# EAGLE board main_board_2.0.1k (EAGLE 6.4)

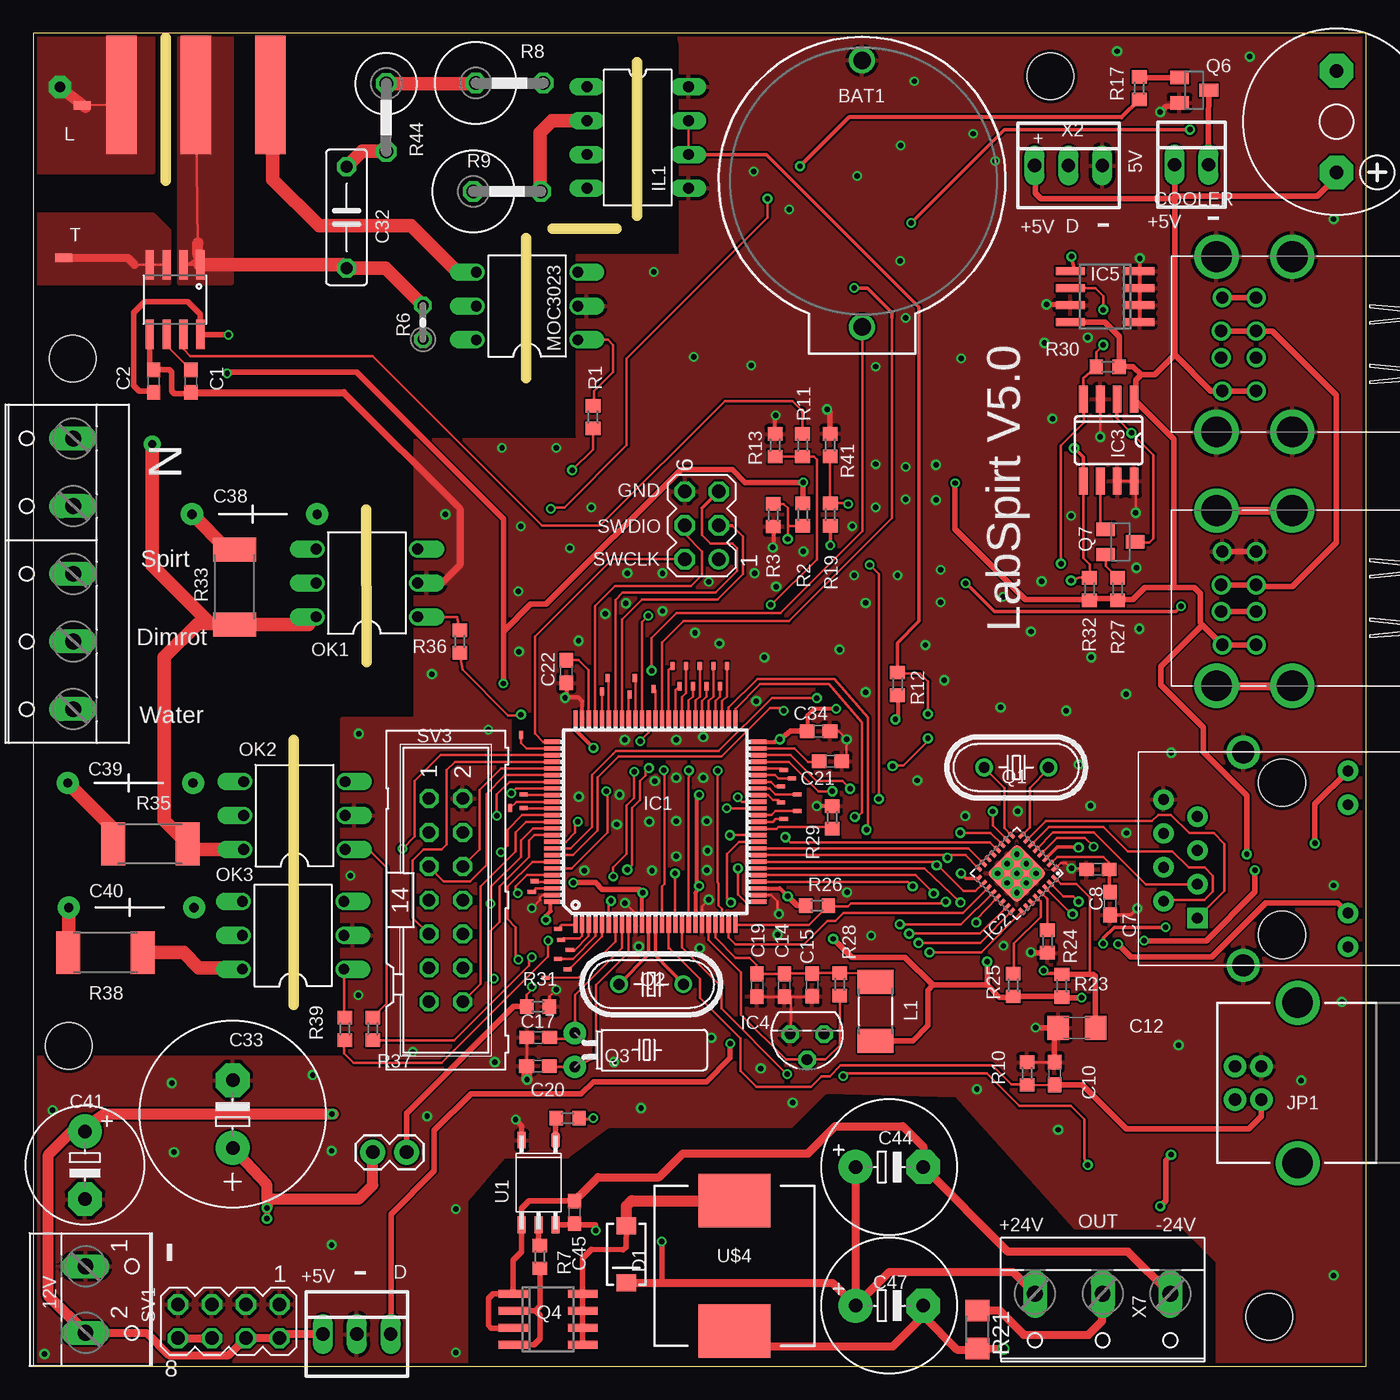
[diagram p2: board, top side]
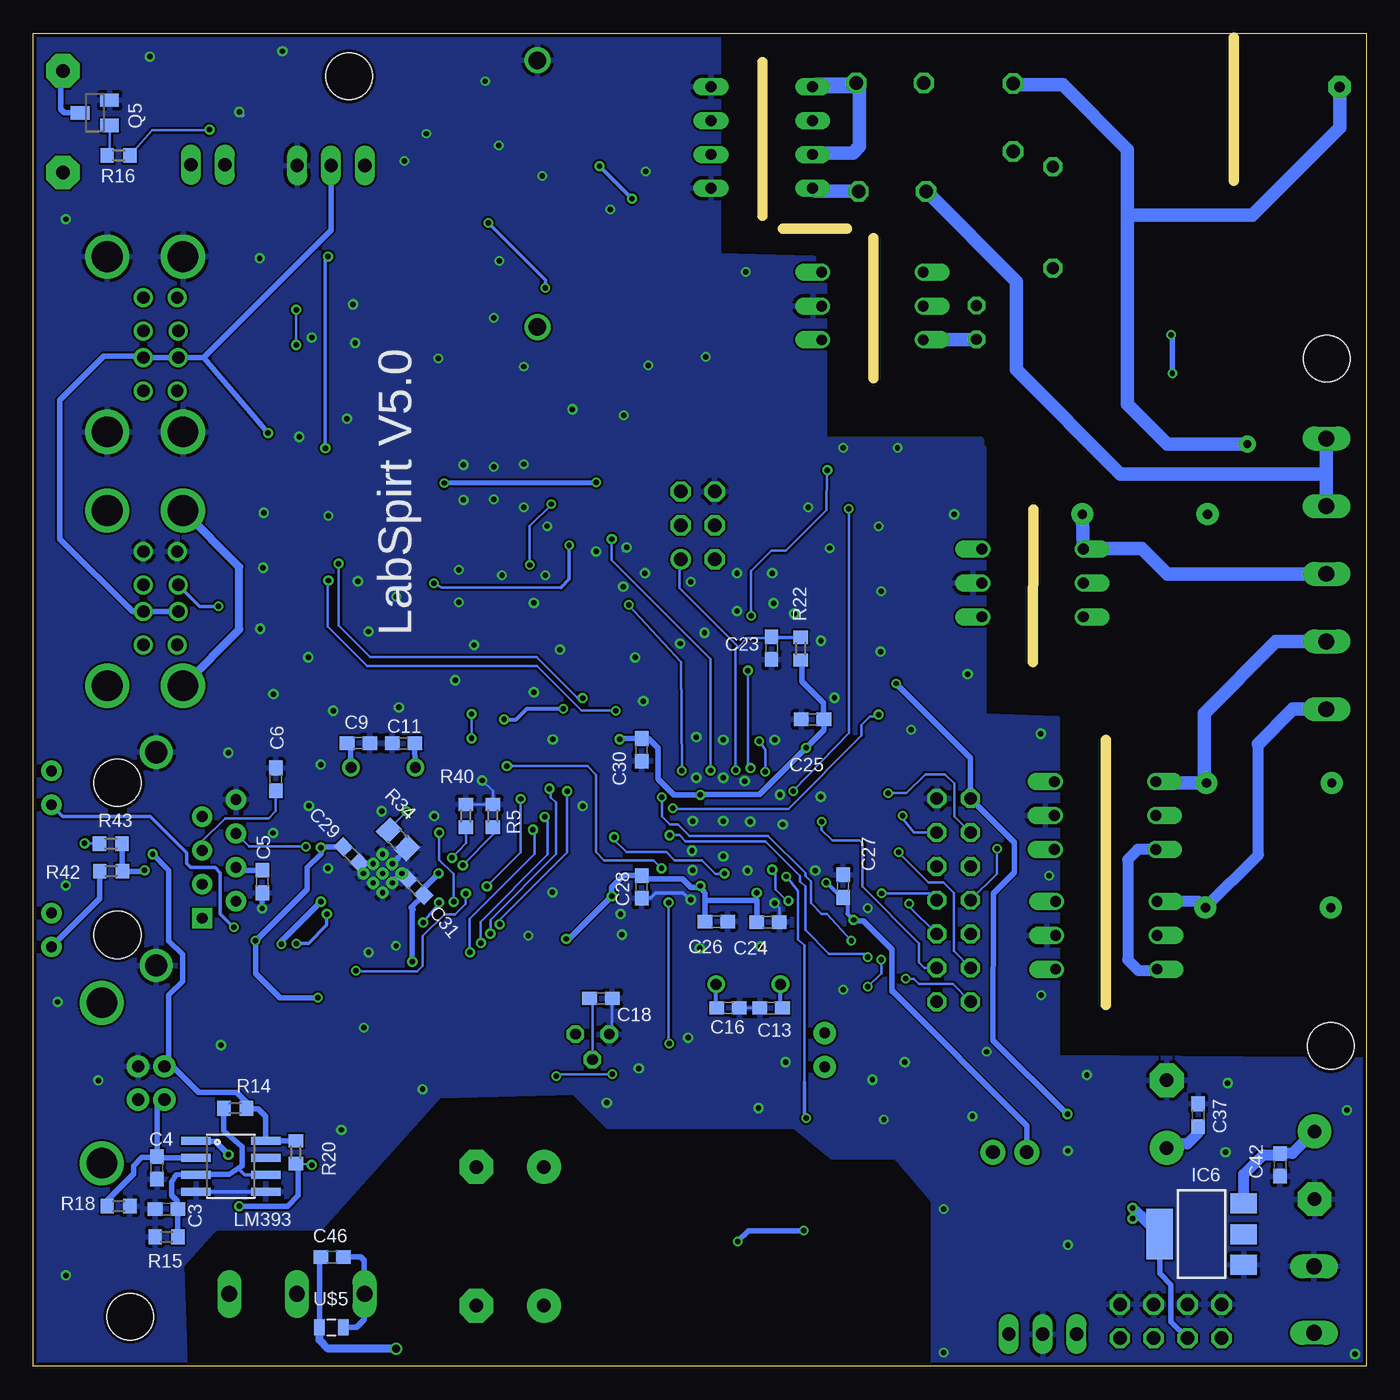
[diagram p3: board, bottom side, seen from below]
Size 100 x 100 mm. Coordinates in mm from the lower left corner, seen from the top.
Outline: 19.53,27.11 19.53,46.98
Outline: 25.02,52.82 24.96,64.29
Outline: 45.3,86.31 45.3,97.83
Outline: 36.97,74.12 36.97,84.62
Outline: 43.76,85.33 38.95,85.33
Outline: 9.94,88.95 9.94,99.66
Outline: 100,100 0,100 0,0 100,0 100,100
Copper layers (1*16): Top 0.035mm / dielectric 1.5mm / Bottom 0.035mm
Design rules "SeeedStudio_2layer_DRU_no_angle_20140221": minimum track width 6mil, minimum drill 12mil, track to track 6mil, track to pad 6mil, pad to pad 6mil, via to via 6mil, smd to smd 0mil, copper to edge 10mil, drill to drill 10mil, minimum pad ring 10mil, minimum via ring 6mil, stop-mask expansion 2mil, vias tented up to drill 100mil, thermal gap 10mil
Net classes: 0 default: width 0.203 mm, drill 0.203 mm, clearance 0.152 mm; 1 GND: width 0.203 mm, drill 0.203 mm, clearance 0.152 mm to class 0; 2 +3V3: width 0.254 mm, drill 0.203 mm, clearance 0.152 mm to class 0, clearance 0.152 mm to class 1; 3 +5V: width 0.406 mm, drill 0.152 mm, clearance 0.203 mm to class 0, clearance 0.203 mm to class 1, clearance 0.203 mm to class 2
Holes 3.5 mm at 76.32,96.76 2.65,24.02 92.73,3.72 2.97,75.6
tRestrict: area 73.8,35 to 76,39.2; 3 lines

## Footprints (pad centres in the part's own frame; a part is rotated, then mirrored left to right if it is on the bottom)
W237-102 = drill 1.194 long: 1 -2.5,-1.27; 2 2.5,-1.27
SO08 = smd 0.61 x 2.21: 1 -1.905,-2.616; 2 -0.635,-2.616; 3 0.635,-2.616; 4 1.905,-2.616; 5 1.905,2.616; 6 0.635,2.616; 7 -0.635,2.616; 8 -1.905,2.616
BATTCOM_20MM_PTH = drill 1.3: 1 20,0; 2 0,0
1X02 = drill 1.016 pad 1.88: 1 0,0; 2 2.54,0
C0603 = smd 1.1 x 1: 1 -0.85,0; 2 0.85,0
1206 = smd 1.6 x 1.8: 1 -1.4,0; 2 1.4,0
C075-032X103 = drill 0.914 octagon: 1 -3.81,0; 2 3.81,0
E5-13 = drill 1.016 pad 2.54: + -2.54,0 | drill 1.016 pad 2.54 octagon: - 2.54,0
CAP-PTH-LARGE = drill 0.7 pad 1.651: 1 -4.826,0; 2 4.572,0
E5-8,5 = drill 1.016 pad 2.54: + -2.54,0 | drill 1.016 pad 2.54 octagon: - 2.54,0
E5-10,5 = drill 1.016 pad 2.54: + -2.54,0 | drill 1.016 pad 2.54 octagon: - 2.54,0
22-23-2021 = drill 1 long: 1 -1.27,0; 2 1.27,0
SMA-DIODE = smd 1.27 x 1.47: A -2.15,0; C 2.15,0
LQFP100 = smd 1.2 x 0.32: 1 -7.75,6; 2 -7.75,5.5; 3 -7.75,5; 4 -7.75,4.5; 5 -7.75,4; 6 -7.75,3.5; 7 -7.75,3; 8 -7.75,2.5; 9 -7.75,2; 10 -7.75,1.5; 11 -7.75,1; 12 -7.75,0.5; 13 -7.75,0; 14 -7.75,-0.5; 15 -7.75,-1; 16 -7.75,-1.5; 17 -7.75,-2; 18 -7.75,-2.5; 19 -7.75,-3; 20 -7.75,-3.5; 21 -7.75,-4; 22 -7.75,-4.5; 23 -7.75,-5; 24 -7.75,-5.5; 25 -7.75,-6; 51 7.75,-6; 52 7.75,-5.5; 53 7.75,-5; 54 7.75,-4.5; 55 7.75,-4; 56 7.75,-3.5; 57 7.75,-3; 58 7.75,-2.5; 59 7.75,-2; 60 7.75,-1.5; 61 7.75,-1; 62 7.75,-0.5; 63 7.75,0; 64 7.75,0.5; 65 7.75,1; 66 7.75,1.5; 67 7.75,2; 68 7.75,2.5; 69 7.75,3; 70 7.75,3.5; 71 7.75,4; 72 7.75,4.5; 73 7.75,5; 74 7.75,5.5; 75 7.75,6 | smd 0.32 x 1.2: 26 -6,-7.75; 27 -5.5,-7.75; 28 -5,-7.75; 29 -4.5,-7.75; 30 -4,-7.75; 31 -3.5,-7.75; 32 -3,-7.75; 33 -2.5,-7.75; 34 -2,-7.75; 35 -1.5,-7.75; 36 -1,-7.75; 37 -0.5,-7.75; 38 0,-7.75; 39 0.5,-7.75; 40 1,-7.75; 41 1.5,-7.75; 42 2,-7.75; 43 2.5,-7.75; 44 3,-7.75; 45 3.5,-7.75; 46 4,-7.75; 47 4.5,-7.75; 48 5,-7.75; 49 5.5,-7.75; 50 6,-7.75; 76 6,7.75; 77 5.5,7.75; 78 5,7.75; 79 4.5,7.75; 80 4,7.75; 81 3.5,7.75; 82 3,7.75; 83 2.5,7.75; 84 2,7.75; 85 1.5,7.75; 86 1,7.75; 87 0.5,7.75; 88 0,7.75; 89 -0.5,7.75; 90 -1,7.75; 91 -1.5,7.75; 92 -2,7.75; 93 -2.5,7.75; 94 -3,7.75; 95 -3.5,7.75; 96 -4,7.75; 97 -4.5,7.75; 98 -5,7.75; 99 -5.5,7.75; 100 -6,7.75
QFN32 = smd 0.6 x 0.3: 1 -2.3,1.75; 2 -2.3,1.25; 3 -2.3,0.75; 4 -2.3,0.25; 5 -2.3,-0.25; 6 -2.3,-0.75; 7 -2.3,-1.25; 8 -2.3,-1.75; 17 2.3,-1.75; 18 2.3,-1.25; 19 2.3,-0.75; 20 2.3,-0.25; 21 2.3,0.25; 22 2.3,0.75; 23 2.3,1.25; 24 2.3,1.75 | smd 0.3 x 0.6: 9 -1.75,-2.3; 10 -1.25,-2.3; 11 -0.75,-2.3; 12 -0.25,-2.3; 13 0.25,-2.3; 14 0.75,-2.3; 15 1.25,-2.3; 16 1.75,-2.3; 25 1.75,2.3; 26 1.25,2.3; 27 0.75,2.3; 28 0.25,2.3; 29 -0.25,2.3; 30 -0.75,2.3; 31 -1.25,2.3; 32 -1.75,2.3 | smd 3.2 x 3.2: G 0,0 | drill 0.4: P$2 -1.016,1.016; P$3 0,1.016; P$4 1.016,1.016; P$5 -1.016,0; P$6 -1.016,-1.016; P$7 0,0; P$8 0,-1.016; P$9 1.016,0; P$10 1.016,-1.016
SO08' = smd 0.66 x 2.032: 1 -1.905,-3.073; 2 -0.635,-3.073; 3 0.635,-3.073; 4 1.905,-3.073; 5 1.905,3.073; 6 0.635,3.073; 7 -0.635,3.073; 8 -1.905,3.073
TO92 = drill 0.813 octagon: 1 -1.27,0; 2 0,1.905; 3 1.27,0
SO-08 = smd 0.6 x 2.2: 1 -1.905,-2.6; 2 -0.635,-2.6; 3 0.635,-2.6; 4 1.905,-2.6; 5 1.905,2.6; 6 0.635,2.6; 7 -0.635,2.6; 8 -1.905,2.6
SOT223 = smd 1.5 x 2: 1 -2.3,-3.15; 2 0,-3.15; 3 2.3,-3.15 | smd 3.8 x 2: 4 0,3.15
DIL8 = drill 0.813 long: 1 -3.81,-3.81; 2 -1.27,-3.81; 3 1.27,-3.81; 4 3.81,-3.81; 5 3.81,3.81; 6 1.27,3.81; 7 -1.27,3.81; 8 -3.81,3.81
USB-B-PTH = drill 0.914 pad 1.676: D+ 0,1.25; D- 1.981,1.25; GND 0,-1.25; VBUS 1.981,-1.25 | drill 2.286: S1 -2.718,-6.02; S2 -2.718,6.02
PAD-220 = smd 0.635 x 1.27: 1 0,0
R2010 = smd 1.8 x 2.7: 1 -2.2,0; 2 2.2,0
DIL06 = drill 0.813 offset: 1 -2.54,-3.81; 2 0,-3.81; 3 2.54,-3.81; 4 2.54,3.81; 5 0,3.81; 6 -2.54,3.81
HC49U-V = drill 0.813: 1 -2.413,0; 2 2.413,0
TC38H = drill 0.813 pad 1.676: 1 -1.27,0; 2 1.27,0
SOT23 = smd 1 x 1.4: 1 -0.95,-1.1; 2 0.95,-1.1; 3 0,1.1
R0603 = smd 1 x 1.1: 1 -0.85,0; 2 0.85,0
0204V = drill 0.813 octagon: 1 -1.27,0; 2 1.27,0
0617V = drill 1.016 octagon: 1 -2.54,0; 2 2.54,0
R1206 = smd 1.6 x 1.803: 1 -1.422,0; 2 1.422,0
R2512 = smd 1.8 x 3.2: 1 -2.8,0; 2 2.8,0
R0805 = smd 1.3 x 1.5: 1 -0.95,0; 2 0.95,0
P0613V = drill 1.016 octagon: 1 -2.54,0; 2 2.54,0
HR911105A = drill 0.813 pad 1.524: G+ 4.953,-6.604; G- 4.953,-4.064; GND -8.89,4.445; NC -6.35,3.175; P4 -8.89,-0.635; P5 -6.35,0.635; RD+ -6.35,-1.905; RD- -8.89,1.905; TD- -8.89,-3.175; Y+ 4.953,6.604; Y- 4.953,4.064 | drill 1.651 pad 2.159: SHIELD0 -2.921,8.001; SHIELD1 -2.921,-8.001 | drill 0.813 pad 1.524 square: TD+ -6.35,-4.445 | hole 3.556: 0,-5.715; 0,5.715
F/CM12P = drill 1.016 pad 2.54 octagon: + 3.81,0; - -3.81,0
MA04-2 = drill 1.016 octagon: 1 -3.81,-1.27; 2 -3.81,1.27; 3 -1.27,-1.27; 4 -1.27,1.27; 5 1.27,-1.27; 6 1.27,1.27; 7 3.81,-1.27; 8 3.81,1.27
MA03-2 = drill 1.016: 1 -2.54,-1.27 | drill 1.016 octagon: 2 -2.54,1.27; 3 0,-1.27; 4 0,1.27; 5 2.54,-1.27; 6 2.54,1.27
ML14 = drill 0.914 octagon: 1 -7.62,-1.27; 2 -7.62,1.27; 3 -5.08,-1.27; 4 -5.08,1.27; 5 -2.54,-1.27; 6 -2.54,1.27; 7 0,-1.27; 8 0,1.27; 9 2.54,-1.27; 10 2.54,1.27; 11 5.08,-1.27; 12 5.08,1.27; 13 7.62,-1.27; 14 7.62,1.27
MY = smd 0.305 x 0.61: P$1 0,0
PANASONIC_SOP5 = smd 0.6 x 1.25: 1 -1.27,-3.175; 2 1.27,-3.175; 3 1.27,3.175; 4 0,3.175; 5 -1.27,3.175
TOP3L = smd 2.286 x 8.89: A1 -5.334,-0.508; A2 0.254,-0.508; G3 5.842,-0.508
CDRH125 = smd 5.4 x 4: 1 0,4.9; 2 0,-4.9
0805 = smd 0.8 x 1.2: 1 -0.9,0; 2 0.9,0
22-23-2031 = drill 1 long: 1 -2.54,0; 2 0,0; 3 2.54,0
W237-5P = drill 1.194 long: 1 -10.16,-0.635; 2 -5.08,-0.635; 3 0,-0.635; 4 5.08,-0.635; 5 10.16,-0.635
85-32003-00X-1 = drill 0.92 pad 1.27: 1-1 2.71,3.5; 1-2 2.71,1; 1-3 2.71,-1; 1-4 2.71,-3.5; 1-5 5.25,3.5; 1-6 5.33,1; 1-7 5.33,-1; 1-8 5.25,-3.5 | drill 2.3 pad 3: M1 0,6.57; M2 0,-6.57; M3 5.68,6.57; M4 5.68,-6.57
W237-133 = drill 1.194 long: 1 -5.08,-0.635; 2 0,-0.635; 3 5.08,-0.635

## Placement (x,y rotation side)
12V  [W237-102]  5.18,4.99 270 top
$1_103_$  ACS712  [SO08]  10.63,80.02 180 top
BAT1  3.3V  [BATTCOM_20MM_PTH]  62.18,97.97 270 top
BOOT  M02PTH  [1X02]  25.47,16.05 0 top
C1  0.01uF  [C0603]  11.82,73.9 90 top
C2  0.1uF  [C0603]  9.03,73.9 270 top
C3  0.1uF  [C0603]  90,11.79 0 bottom
C4  0.1uF  [C0603]  90.72,14.88 90 bottom
C5  0.1uF  [C0603]  82.82,36.36 270 bottom
C6  0.1uF  [C0603]  81.8,44.03 90 bottom
C7  2.2uF  [C0603]  80.79,34.71 90 top
C8  0.1uF  [C0603]  79.87,37.27 0 top
C9  22pF  [C0603]  75.61,46.75 0 bottom
C10  0.1uF  [C0603]  76.62,21.96 270 top
C11  22pF  [C0603]  72.22,46.73 180 bottom
C12  10uF  [1206]  78.29,25.39 0 top
C13  22pF  [C0603]  44.64,26.88 180 bottom
C14  1uF  [C0603]  56.35,28.58 90 top
C15  1uF  [C0603]  58.43,28.6 270 top
C16  22pF  [C0603]  47.88,26.88 0 bottom
C17  6.8pF  [C0603]  37.88,24.66 180 top
C18  0.1uF  [C0603]  57.42,27.6 180 bottom
C19  0.1uF  [C0603]  54.29,28.58 270 top
C20  6.8pF  [C0603]  37.86,22.52 180 top
C21  2.2uF  [C0603]  59.81,45.38 0 top
C22  2.2uF  [C0603]  39.99,52.12 270 top
C23  0.1uF  [C0603]  44.62,53.89 270 bottom
C24  0.1uF  [C0603]  44.88,33.31 180 bottom
C25  0.1uF  [C0603]  41.53,48.53 180 bottom
C26  0.1uF  [C0603]  48.76,33.35 180 bottom
C27  0.1uF  [C0603]  39.24,36.02 90 bottom
C28  0.1uF  [C0603]  54.36,35.96 90 bottom
C29  0.1uF  [C0603]  76.14,38.37 315 bottom
C30  0.1uF  [C0603]  54.36,46.24 90 bottom
C31  0.1uF  [C0603]  71.31,35.96 135 bottom
C32  0.01uF  [C075-032X103]  23.51,86.19 90 top
C33  4700uF/6.3V  [E5-13]  14.96,18.91 90 top
C34  4.7uF  [C0603]  58.92,47.64 0 top
C37  0.1uF  [C0603]  12.61,18.84 270 bottom
C38  0.01uF  [CAP-PTH-LARGE]  16.47,63.92 180 top
C39  0.01uF  [CAP-PTH-LARGE]  7.15,43.75 180 top
C40  0.01uF  [CAP-PTH-LARGE]  7.23,34.4 180 top
C41  1000uF/10V  [E5-8,5]  3.87,15.08 270 top
C42  0.1uF  [C0603]  6.46,15.1 90 bottom
C44  220uF/35  [E5-10,5]  64.22,14.95 0 top
C45  0.1uF  [C0603]  40.6,11.54 270 top
C46  0.1uF  [C0603]  77.58,8.19 0 bottom
C47  220uF/63  [E5-10,5]  64.22,4.53 0 top
COOLER  22-23-2021  [22-23-2021]  86.9,90.14 0 top
D1  SS36  [SMA-DIODE]  44.49,8.39 270 top
IC1  STM32F407  [LQFP100]  46.67,40.85 90 top
IC2  KSZ8051RNL  [QFN32]  73.79,36.97 225 top
IC3  DS2428  [SO08']  80.68,69.47 180 top
IC4  LM336LP  [TO92]  58.05,24.91 180 top
IC5  24LC64SN  [SO-08]  80.4,80.25 90 top
IC6  LD117AS33TR  [SOT223]  12.34,9.91 90 bottom
IL1  MCT62  [DIL8]  45.35,92.18 270 top
JP1  USB-B  [USB-B-PTH]  92.14,21.25 180 top
L  PAD-220  [PAD-220]  3.68,94.6 270 top
L1  47u  [R2010]  63.2,26.62 90 top
LM393  LM393  [SO08]  85.18,15 270 bottom
MOC3023  IL410  [DIL06]  37.05,79.54 90 top
OK1  MOC3063  [DIL06]  25.03,58.76 90 top
OK2  MOC3063  [DIL06]  19.6,41.31 90 top
OK3  MOC3063  [DIL06]  19.49,32.32 90 top
Q1  25Mhz  [HC49U-V]  73.75,44.92 180 top
Q2  25Mhz  [HC49U-V]  46.36,28.65 0 top
Q3  [TC38H]  40.63,23.73 270 top
Q4  IRF7103  [SO-08]  38.62,3.52 270 top
Q5  BC847  [SOT23]  95.38,94.03 90 bottom
Q6  BC847  [SOT23]  87.1,95.73 270 top
Q7  BSS84  [SOT23]  81.56,61.84 270 top
R1  200  [R0603]  41.99,71.21 90 top
R2  4.7k  [R0603]  57.74,63.9 270 top
R3  4.7k  [R0603]  55.52,63.84 270 top
R4  200  [R0603]  40.09,18.61 180 top
R5  1k  [R0603]  65.52,41.29 270 bottom
R6  180  [0204V]  29.24,78.31 90 top
R7  [R0603]  38.01,8.19 270 top
R8  33k  [0617V]  35.73,96.27 0 top
R9  33k  [0617V]  35.55,88.14 0 top
R10  10k  [R0603]  74.56,21.96 90 top
R11  4.7k  [R0603]  57.71,69.09 270 top
R12  4.3k  [R0603]  64.84,51.19 270 top
R13  4.7k  [R0603]  55.65,69.09 90 top
R14  15k  [R0603]  84.86,19.34 0 bottom
R15  1.5k  [R0603]  90.01,9.7 0 bottom
R16  1k  [R0603]  93.6,90.83 180 bottom
R17  1k  [R0603]  82.98,95.88 90 top
R18  1M  [R0603]  93.61,12 180 bottom
R19  4.7k  [R0603]  59.8,63.89 90 top
R20  4.3k  [R0603]  80.3,16.05 90 bottom
R21  0  [R1206]  70.83,2.76 270 top
R22  10k  [R0603]  42.43,53.84 90 bottom
R23  10k  [R0603]  77.17,28.55 90 top
R24  1k  [R0603]  76.09,31.86 90 top
R25  4.7k  [R0603]  73.52,28.59 90 top
R26  1k  [R0603]  58.8,34.56 180 top
R27  1R  [R0603]  81.34,58.3 90 top
R28  4.3k  [R0603]  60.5,28.64 270 top
R29  100R  [R0603]  59.95,41.16 90 top
R30  4.3k  [R0603]  80.6,74.97 180 top
R31  100R  [R0603]  37.87,26.99 0 top
R32  4.3k  [R0603]  79.24,58.31 90 top
R33  39  [R2512]  15.1,58.46 90 top
R34  6.49k  [R0805]  72.64,39.52 135 bottom
R35  39  [R2512]  8.78,39.18 180 top
R36  200  [R0603]  31.99,54.37 90 top
R37  200  [R0603]  25.46,25.31 90 top
R38  39  [R2512]  5.42,31.03 180 top
R39  200  [R0603]  23.38,25.31 90 top
R40  1k  [R0603]  67.55,41.29 90 bottom
R41  4.7k  [R0603]  59.78,69.1 90 top
R42  220  [R0603]  94.17,37.15 0 bottom
R43  220  [R0603]  94.2,39.2 0 bottom
R44  39  [P0613V]  26.48,93.69 270 top
RJ1  HR911105A  [HR911105A]  93.69,38.06 0 top
SG1  F/CM12P  [F/CM12P]  97.78,93.37 270 top
SV1  [MA04-2]  14.67,3.37 180 top
SV2  [MA03-2]  50.15,63.08 90 top
SV3  [ML14]  30.95,34.96 270 top
T  PAD-220  [PAD-220]  2.28,83.15 270 top
TP1  PTR1MY0012X0024  [MY]  39.59,31.97 90 top
TP2  PTR1MY0012X0024  [MY]  40.25,31.23 90 top
TP3  PTR1MY0012X0024  [MY]  39.36,30.57 90 top
TP4  PTR1MY0012X0024  [MY]  40.07,29.76 90 top
TP5  PTR1MY0012X0024  [MY]  38.44,29.15 90 top
TP6  PTR1MY0012X0024  [MY]  56.3,41.06 90 top
TP7  PTR1MY0012X0024  [MY]  57.32,41.67 90 top
TP8  PTR1MY0012X0024  [MY]  56.1,42.28 90 top
TP9  PTR1MY0012X0024  [MY]  57.32,42.89 90 top
TP10  PTR1MY0012X0024  [MY]  56.1,43.5 270 top
TP11  PTR1MY0012X0024  [MY]  56.91,44.11 90 top
TP12  PTR1MY0012X0024  [MY]  56.3,44.72 90 top
TP13  PTR1MY0012X0024  [MY]  52.03,52.54 180 top
TP14  PTR1MY0012X0024  [MY]  46.55,50.81 0 top
TP15  PTR1MY0012X0024  [MY]  45.12,51.63 0 top
TP16  PTR1MY0012X0024  [MY]  44.72,50.41 0 top
TP17  PTR1MY0012X0024  [MY]  43.09,51.63 0 top
TP18  PTR1MY0012X0024  [MY]  42.68,50.61 0 top
TP19  PTR1MY0012X0024  [MY]  36.59,47.36 0 top
TP20  PTR1MY0012X0024  [MY]  36.79,42.89 90 top
TP21  PTR1MY0012X0024  [MY]  35.78,41.87 180 top
TP22  PTR1MY0012X0024  [MY]  36.79,41.87 270 top
TP23  PTR1MY0012X0024  [MY]  37.6,36.39 90 top
TP24  PTR1MY0012X0024  [MY]  37.4,35.57 90 top
TP25  PTR1MY0012X0024  [MY]  39.36,32.8 90 top
TP26  PTR1MY0012X0024  [MY]  51.52,51.02 0 top
TP27  PTR1MY0012X0024  [MY]  51.02,52.54 0 top
TP28  PTR1MY0012X0024  [MY]  50.51,51.02 0 top
TP29  PTR1MY0012X0024  [MY]  50,52.54 0 top
TP30  PTR1MY0012X0024  [MY]  49.49,51.02 0 top
TP31  PTR1MY0012X0024  [MY]  48.98,52.54 0 top
TP32  PTR1MY0012X0024  [MY]  48.48,51.02 0 top
TP33  PTR1MY0012X0024  [MY]  47.97,52.54 0 top
U1  LTV-155E  [PANASONIC_SOP5]  37.91,13.78 180 top
U$1  BTA-41  [TOP3L]  11.94,95.9 0 top
U$4  [CDRH125]  52.59,7.53 0 top
U$5  DIODE_0806  [0805]  77.64,2.91 0 bottom
X1  22-23-2031  [22-23-2031]  24.27,2.4 0 top
X2  22-23-2031  [22-23-2031]  77.66,90.08 0 top
X3  [W237-5P]  2.35,59.45 90 top
X5  USB_3PSHIELD-85-32003-00X-1  [85-32003-00X-1]  94.45,57.62 180 top
X6  USB_3PSHIELD-85-32003-00X-1  [85-32003-00X-1]  94.45,76.67 180 top
X7  [W237-133]  80.23,4.79 180 top

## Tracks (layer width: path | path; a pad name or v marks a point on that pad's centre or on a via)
1WIRE  (via drill 0.41 pad 0.76)
  Top 0.203: 81.32,71.08 v82.38,70.02 84.04,68.36 84.04,62.09 83.73,61.79 82.71,61.79 Q7.3 | 81.32,71.08 IC3.2 81.24,72.47 81.24,71.16 81.32,71.08
  Top 0.406: X5.1-6 X5.1-2
  Bottom 0.203: 91.85,75.78 X6.1-2
  Bottom 0.406: X6.1-2 X6.1-6 87.23,75.67 | v82.38,70.02 87.23,75.67 | X5.1-6 92.56,56.62 98.01,62.06 98.01,72.48 94.7,75.78 91.85,75.78 | X2.2 77.66,85.24 87.23,75.67
+3V3  (via drill 0.41, 0.41 pad 0.76)
  Top 0.254: IC2.17 69.99,36.58 v69.6,36.97 | IC2.3 76.85,38.97 78.14,38.97 v78.42,38.91 | 40.67,47.73 IC1.75
  Top 0.305: IC1.19 49.67,35.5 v49.95,36.03 49.77,36.34 49.77,42.69 v49.95,42.87 | IC1.50 55.63,46.85 v56.01,47.04 | 40.67,47.73 v42.02,46.39 | R12.2 64.88,50.29 64.88,48.73 v64.68,48.53 | 58.14,47.68 C34.1 58.08,47.65 58.08,48.83 58.56,49.31 v60.24,49.31 | IC1.28 56.01,35.85 v56.6,35.25 | v38.46,33.48 38.46,33.78 38.82,34.15 38.82,34.75 IC1.100 | IC1.11 45.67,35.46 v45.72,35.51
  Top 0.406: v56.01,47.04 56.81,47.65 C34.1 | 71.57,28.59 67.5,28.59 | v60.01,32.06 60.03,32.06 61.41,30.69 65.41,30.69 67.5,28.59 | v71.57,30.36 71.57,28.59 | 71.57,28.59 72.49,27.66 73.44,27.66 R25.1 77.13,27.74 R23.1 77.22,27.65 v78.65,27.65 | v17.52,11.88 v17.52,11.06 | R26.2 57.29,34.56 v56.6,35.25 | L1.1 65.98,24.42 67.12,25.57 67.12,28.21 67.5,28.59 | v91.66,37.2 91.66,35.57 88,31.91 v83.33,31.91 | v40.5,36.28 42.18,36.28 42.69,35.78 45.46,35.78 v45.72,35.51
  Top 0.61: SV1.8 SV1.6
  Top 0.813: 17.53,12.54 v17.52,11.88 | 17.53,12.54 17.53,13.59 C33.+ | 17.53,12.54 24.43,12.54 25.46,13.58 BOOT.1
  Bottom 0.254: 93.35,37.17 R42.2 | v78.42,38.91 78.42,38.85
  Bottom 0.305: 45.72,34.93 v45.72,35.51 | v38.46,33.48 38.92,33.95 IC1.100 C27.1 39.39,35.17 v40.5,36.28 | v64.68,48.53 63.77,48.53 62.95,49.34 60.26,49.34 v60.24,49.31
  Bottom 0.406: C24.2 45.72,33.77 45.72,34.93 49.59,34.93 | C26.2 49.59,33.81 49.59,34.93 | C30.2 55.76,47.09 v56.01,47.04 | 54.12,47.32 54.22,47.22 C30.2 | 40.6,48.34 C25.1 | 76.92,38.89 76.82,38.89 C29.1 78.39,38.97 v78.42,38.91 78.42,38.44 79.46,37.4 79.46,35.78 v83.33,31.91 83.33,29.48 81.5,27.65 v78.65,27.65 | 49.75,35.64 v49.95,36.03 | v71.57,30.36 71.57,34.22 71.5,34.28 71.64,34.42 70.73,35.33 C31.1 70.71,35.86 v69.6,36.97 | C30.2 53.85,47.09 53.12,46.37 53.12,44.06 51.93,42.87 v49.95,42.87 49.93,42.89 45.53,42.89 v42.03,46.39 v42.02,46.39 40.68,47.73 C25.1 | 49.59,34.93 49.59,35.47 v49.95,36.03 | R43.2 93.35,37.17 | IC6.4 15.49,6.96 14.64,6.11 14.64,3.34 SV1.6 | C37.2 12.61,17.49 | 14.66,16.67 C33.+ | C25.1 IC1.75 40.7,48.62 40.7,49.75 42.33,51.37 42.33,52.88 R22.1 42.42,53 | R42.2 93.28,37.11 91.75,37.11 v91.66,37.2 | v60.01,32.06 59.79,32.06 v56.6,35.25 56.61,35.59 56.61,35.91 55.7,36.81 C28.2 54.22,36.76 54.02,36.55 51.28,36.55 50.66,35.93 50.05,35.93 v49.95,36.03 | v38.46,33.48 38.37,33.39 37.71,33.39 35.57,31.25 35.57,28.11 35.52,28.11 25.47,18.05 BOOT.1
  Bottom 0.813: v17.52,11.88 IC6.4 | 12.61,17.49 13.42,16.67 14.66,16.67
+3V3A
  Top 0.203: L1.2 63.14,29.46 R28.1 58.47,29.49 C15.1 56.38,29.45 C14.2 C19.1 54.26,29.47 54.26,30.11 53.72,30.64 52.69,30.64 51.17,32.16 IC1.22
+5V  (via drill 0.41, 0.41 pad 0.76)
  Top 0.406: R27.1 81.48,57.59 | R32.1 79.5,57.59 81.2,57.59 R27.1 | 81.56,75.07 81.5,75.01 | 81.24,57.61 R27.1 | 12.49,77.6 $1_103_$.8 | 85.59,58.41 87.11,58.41 87.54,57.98 87.54,55.78 87.71,55.61 | 85.59,58.41 85.59,69.54 IC3.1 82.72,72.67 82.72,73.98 83.12,74.38 | 18.78,2.4 SV1.2 | 74.9,90.3 X2.1 | X2.1 75.12,89.7 | 79.28,57.42 R32.1 | R32.1 79.17,57.52 74.44,57.52 69.15,62.8 v69.15,66.26 | 85.59,58.41 83.4,58.41 82.51,57.52 81.41,57.52 R27.1 | v91.05,38.42 91.05,42.84 87.8,46.09 87.8,47.92 84.59,51.12 84.59,52.49 87.71,55.61 | X2.1 75.2,90 75.2,88 75.6,87.59 85.43,87.59 85.63,87.39 | 87.71,55.61 X5.1-5 X5.1-1 | v35.27,51.22 35.27,55.13 | 35.27,55.13 37.3,57.16 38.47,57.16 48.58,67.27 52.44,67.27 53.4,66.31 v57.75,66.31 R2.1 | 35.27,55.13 35.27,63.56 24.24,74.59 14.64,74.59 v14.54,74.49 | v14.64,77.38 12.56,77.38 $1_103_$.8 | $1_103_$.8 12.53,78.93 11.59,79.87 8.34,79.87 7.53,79.06 7.53,73.57 7.94,73.16 8.92,73.16 C2.2 | IC5.8 80.38,78.35 81.5,77.23 81.5,75.01 | 81.5,75.01 R30.1 | X6.1-1 X6.1-5 88.35,73.17 85.63,75.88 | COOLER.1 85.63,87.59 | 85.63,87.59 85.63,87.39 | 85.63,87.39 85.63,75.88 | SG1.+ 97.78,89.24 96.33,87.8 85.84,87.8 85.63,87.59 | 85.63,75.88 84.14,74.38 83.12,74.38 | 81.5,75.01 82.5,75.01 83.12,74.38
  Top 0.61: 12V.2 8.51,2.49 10.17,0.83 14.67,0.83 SV1.4 SV1.2 | X1.1 18.78,2.4
  Top 0.813: 12V.2 1.13,5.28 1.13,15.86 2.88,17.62 C41.+ 4.08,17.82 4.08,18.1 5.3,18.91 v22.42,18.91 22.52,18.91
  Bottom 0.406: IC6.3 | 89.83,22.57 89.42,22.36 87.59,20.54 84.75,20.54 84.01,19.8 R14.2 83.98,19.32 83.12,19.32 82.56,18.76 LM393.8 82.56,16.83 81.85,16.83 81.85,16.9 R20.2 | 89.83,22.57 90.03,22.36 JP1.VBUS | v91.05,38.42 89.83,37.2 89.83,31.91 88.81,30.9 88.81,28.87 89.83,27.85 89.83,22.57 | v22.42,18.91 28,24.45 27.95,35.47 26.38,37.05 26.38,39.28 SV3.1 29.68,45.63 v35.27,51.22 | v69.15,66.26 v57.75,66.31 | v14.54,74.49 14.54,77.28 v14.64,77.38
  Bottom 0.813: C41.+ 5.54,15.95 C42.2 6.55,15.86 7.73,15.86 9.19,14.4 IC6.3
+24V  (via drill 0.41)
  Top 0.406: U1.5 40.51,10.6 | 40.51,10.6 C45.2 | 40.51,10.6 42.18,10.6 v42.2,10.17 | v47.16,9.36 47.16,6.45 47.36,6.24
  Top 0.61: D1.C 47.36,6.24 59.97,6.24 C47.+ | C44.+ C47.+ | C47.+ 64.22,7.07 73.5,7.07 X7.3
  Bottom 0.406: U$5.2 75.76,2.91 75.2,3.47 75.2,5.37 X7.3 75.2,5.47 75.2,7.94 75.45,8.19 C46.2 | v42.2,10.17 46.34,10.17 v47.16,9.36
-24
  Top 0.406: Q4.3 35.99,2.86 34.35,2.86 34.15,3.06 34.15,5.09 34.48,5.42 Q4.1 35.98,5.47 35.98,7.94 36.64,8.6 U1.3 36.64,11.85 37.2,12.41 40.59,12.41 C45.1
  Top 0.61: X7.1 82.13,8.6 73.11,8.6 C44.- 66.76,16.47 65.24,18 60.16,18 58.13,15.96 48.73,15.96 46.95,14.19 42.37,14.19 40.59,12.41
ADC_5  (via drill 0.41 pad 0.76)
  Top 0.203: R2.2 56.61,63.05 | v56.61,62.05 56.61,63.05 | IC1.18 49.17,43.66 v49.19,44.69 | 56.61,63.05 56.61,64.38 56.3,64.68 55.53,64.68 R3.1
  Bottom 0.203: 56.61,62.12 v56.61,62.05 v56.6,62.05 56.6,60.47 49.19,53.05 v49.19,44.69 49.19,44.64
ADC_220  (via drill 0.41)
  Top 0.203: R13.1 R11.2 58.58,68.24 58.79,68.03 58.79,60.52 v55.33,57.11 | IC1.23 51.67,34.3 51.42,34.56 51.42,36.18 51.35,36.34 v51.35,44.67
  Top 0.305: 57.72,68.25 R11.2
  Bottom 0.203: v55.33,57.11 51.4,52.84 v51.35,44.67
ADC_SPIRT_CONC
  Top 0.203: IC1.15 47.67,31.35 47.73,31.35 50,29.07 50,27.65 53.05,24.6 53.05,22.16 54.27,20.94 58.33,20.94 59.14,21.75 59.75,21.75 60.57,22.57 71.95,22.57 73.37,21.15 74.6,21.15 R10.1 | 74.57,20.94 R10.1 | R10.1 76.57,21.06 C10.2
  Top 0.406: JP1.D+ 92.14,18.73 91.2,17.79 82,17.79 78.69,21.11 C10.2
BEEP  (via drill 0.41, 0.41 pad 0.76)
  Top 0.203: IC1.62 47.17,54.29 48.78,55.89 56.71,55.89 64.43,63.61 64.43,78.65
  Top 0.254: 64.43,78.65 64.43,79.06 62.6,80.89 v61.58,80.89 | v86.78,92.77 72.86,92.77 v65.85,85.76
  Bottom 0.203: R16.1 91.06,92.72 86.83,92.72 v86.78,92.77
  Bottom 0.254: v61.58,80.89 61.58,81.5 v65.85,85.76
BOOT0  (via drill 0.41)
  Top 0.203: 38.88,37.87 IC1.94 37.44,37.85 35.57,35.98 35.57,33.54 36.18,32.93 36.18,30.7 v36.39,30.49 | 37.4,26.75 R31.1 | 37.1,27.06 R31.1 | v37.4,28.46 37.4,28.26 36.99,27.85 36.99,27.02 R31.1
  Top 0.406: R31.1 36.03,26.99 28.01,18.96 BOOT.2
  Bottom 0.203: v36.39,30.49 36.39,29.48 v37.4,28.46
BOOT1
  Top 0.203: IC1.37 54.52,40.31 55.76,40.31 55.89,40.45 59.81,40.45 R29.1
CONFIG0
  Top 0.203: IC2.28 75.34,35.07 75.58,34.86 75.58,33.72 73.57,31.71 73.57,29.49 R25.2
CONFIG1
  Top 0.203: 75.63,35.45 75.63,35.48 IC2.29 76,35.12 76.01,35.12 76.09,35.04 R24.2
COOLER  (via drill 0.41, 0.41 pad 0.76)
  Top 0.203: v55.08,87.59 55.08,86.17 44.51,75.6 44.51,69.1 39.84,64.43 38.93,64.43 v38.82,64.33 | v42.99,43.14 43.09,42.84 43.09,40.04 40.39,37.35 IC1.95
  Top 0.305: R17.1 81.64,93.69 61.18,93.69 v57.52,90.03
  Bottom 0.203: v38.82,64.33 38.82,47.51 v42.99,43.14
  Bottom 0.305: v57.52,90.03 v55.08,87.59
CS  (via drill 0.41)
  Top 0.203: IC1.83 36.23,43.35 v35.88,42.99
  Bottom 0.203: v35.88,42.99 34.51,42.99 33.08,44.41 31.61,44.41 30.9,43.7 30.9,41.26 SV3.3
DC
  Top 0.203: IC1.81 35.41,44.35 34,42.94 34,37.61 32.78,36.39 30.8,36.39 SV3.5
DIMROT  (via drill 0.41, 0.41 pad 0.76)
  Top 0.203: IC1.36 v52.26,39.84 | 25.49,24.44 R37.1 31.57,24.46 37.2,30.09 37.2,30.49 v37.4,30.7
  Bottom 0.203: v52.26,39.84 51.52,39.84 51.07,39.38 45.07,39.38 42.48,36.79 42.48,36.39 42.08,35.98 42.08,32.73 40.3,30.95 37.66,30.95 v37.4,30.7
DRAIN
  Top 0.406: D1.A 44.46,8.93 44.26,8.73 41.87,8.75 41.22,8.1 Q4.8 Q4.7 Q4.6 Q4.5
  Top 0.813: D1.A 44.49,12 44.89,12.41 52.21,12.41 U$4.1
ETH_CLK
  Top 0.203: IC2.19 69.74,33.99 60.77,33.99 60.2,33.42 59.56,33.42 57.81,31.66 52.69,31.66 52.17,32.18 IC1.24
ETH_CRS  (via drill 0.41 pad 0.76)
  Top 0.203: IC2.18 70.69,35.64 69.79,35.64 67.8,37.63 | 67.8,37.63 67.58,37.85 IC1.32 | v67.78,37.58 67.93,37.53 67.8,37.63
  Bottom 0.203: R5.2 65.47,39.94 v67.78,37.58
ETH_MDC  (via drill 0.41 pad 0.76)
  Top 0.203: IC2.12 72.3,38.77 71.77,39.31 56.81,39.31 v56.43,39.69 | v48.15,36.97 48.15,33.12 IC1.16
  Bottom 0.203: v48.15,36.97 48.17,36.94 48.83,36.94 49.85,37.96 51.88,37.96 52.49,38.57 55.51,38.57 56.43,39.48 v56.43,39.69
ETH_MDIO  (via drill 0.41 pad 0.76)
  Top 0.203: IC1.25 58.19,33.1 R26.1 | v68.46,34.84 68.39,34.76 68.34,34.71 61.33,34.71 61.13,34.51 59.71,34.51 | IC2.11 71.8,40.02 v69.55,40.02
  Top 0.254: 59.71,34.51 R26.1
  Bottom 0.203: v68.46,34.84 68.47,36.92 69.55,38 v69.55,40.02
ETH_RX_0  (via drill 0.41 pad 0.76)
  Top 0.203: IC2.16 69.94,38.35 68.16,38.35 | 68.16,38.35 IC1.33 | v68.59,38.14 68.54,38.32 68.16,38.35
  Bottom 0.203: R40.1 67.53,39.26 v68.59,38.14
ETH_RX_1
  Top 0.203: IC2.15 70.15,38.85 IC1.34
ETH_RX_ER  (via drill 0.41 pad 0.76)
  Top 0.203: IC2.20 69.61,33.15 v65.01,33.15 | IC1.47 56.69,45.35 58.9,43.13 v59.95,43.13 59.91,43.09
  Bottom 0.203: v59.95,43.13 59.95,38.56 65.01,33.49 v65.01,33.15
ETH_TX_0  (via drill 0.41 pad 0.76)
  Top 0.203: IC2.24 71.04,31.75 v66.41,31.75 | IC1.51 52.67,49.32 54.52,51.17 59.7,51.17 62.18,48.29 62.18,41.55 61.84,41.21 v61.63,41.21
  Bottom 0.203: v61.63,41.21 61.41,40.98 61.41,38.39 66.46,33.34 66.46,31.8 v66.41,31.75
ETH_TX_1  (via drill 0.41 pad 0.76)
  Top 0.203: IC2.25 71.12,31.05 v67.23,31.05 | IC1.52 52.17,49.43 54.32,51.58 60.12,51.58 62.62,48.67 62.62,40.36 v62.51,40.25
  Bottom 0.203: v62.51,40.25 62.39,40.13 62.39,38.42 67.27,33.54 67.27,31.09 v67.23,31.05
ETH_TX_EN  (via drill 0.41 pad 0.76)
  Top 0.203: IC2.23 71.03,32.45 v65.71,32.45 | IC1.48 56.8,45.85 58.74,43.9 60.7,43.9 v61.28,43.32
  Bottom 0.203: v61.28,43.32 61.18,43.22 61.18,42.69 60.77,42.28 60.77,38.42 65.71,33.48 v65.71,32.45
FLOOD  (via drill 0.41, 0.41 pad 0.76)
  Top 0.203: IC1.17 48.67,31.41 51.63,28.46 51.63,26.84 v56.55,21.91 | v79.11,15.1 78.85,15.56 78.85,18.5 77.84,19.52 73.98,19.52 71.54,21.96 60.97,21.96 v60.77,21.75
  Top 0.406: v84.54,12 84.95,12.41 84.95,15.46 v85.36,15.86
  Bottom 0.203: v79.11,15.1 79.23,15.15 R20.1 | v56.55,21.91 60.62,21.91 v60.77,21.75
  Bottom 0.406: v85.36,15.86 86.37,16.88 87.77,16.88 LM393.1 | v84.54,12 80.94,12 80.12,12.81 80.12,14.98 R20.1
G1
  Top 0.203: IC1.1 39.65,33.1 TP25.P$1
G2
  Top 0.203: IC1.2 41.17,32.28 40.98,32.09 39.74,32.09 TP1.P$1
G3
  Top 0.203: IC1.3 41.67,32.28 40.6,31.2 TP2.P$1
G4
  Top 0.203: IC1.4 42.17,32.27 40.48,30.57 TP3.P$1
G5
  Top 0.203: IC1.5 42.67,32.26 40.35,29.93 TP4.P$1
G6
  Top 0.203: IC1.7 43.67,31.86 40.93,29.17 TP5.P$1
G7
  Top 0.203: IC1.38 55.48,40.85 55.69,41.06 TP6.P$1
G8
  Top 0.203: IC1.39 55.37,41.35 55.69,41.67 TP7.P$1
G10
  Top 0.203: IC1.42 55.12,42.85 55.49,42.48 55.89,42.48 TP8.P$1
G11
  Top 0.203: IC1.43 55.23,43.35 55.69,42.89 TP9.P$1
G12
  Top 0.203: IC1.44 55.34,43.85 55.69,43.5 TP10.P$1
G13
  Top 0.203: IC1.45 55.65,44.35 55.89,44.11 TP11.P$1
G14
  Top 0.203: IC1.46 56.17,44.85 TP12.P$1
G15
  Top 0.203: IC1.53 51.67,49.9 52.03,50.25 TP13.P$1
G16
  Top 0.203: IC1.63 46.67,50.68 TP14.P$1
G17
  Top 0.203: IC1.66 45.17,51.58 TP15.P$1
G18
  Top 0.203: IC1.67 44.67,50.36 TP16.P$1
G19
  Top 0.203: IC1.70 43.17,51.54 TP17.P$1
G20
  Top 0.203: IC1.71 42.67,50.4 TP18.P$1
G21
  Top 0.203: IC1.77 36.99,46.35 36.59,46.75 TP19.P$1
G22
  Top 0.203: IC1.84 36.83,42.85 TP20.P$1
G23
  Top 0.203: IC1.85 36.25,42.35 TP21.P$1
G24
  Top 0.203: IC1.86 36.82,41.85 TP22.P$1
G25
  Top 0.203: IC1.97 37.64,36.35 TP23.P$1
G26
  Top 0.203: IC1.98 37.67,35.85 TP24.P$1
G27
  Top 0.203: IC1.54 51.17,49.9 51.52,50.25 TP26.P$1
G28
  Top 0.203: IC1.55 50.67,49.91 51.02,50.25 TP27.P$1
G29
  Top 0.203: IC1.56 50.17,49.92 50.51,50.25 TP28.P$1
G30
  Top 0.203: IC1.57 49.67,49.93 50,50.25 TP29.P$1
G31
  Top 0.203: IC1.58 49.17,49.94 49.49,50.25 TP30.P$1
G32
  Top 0.203: IC1.59 48.67,50.2 48.98,50.51 TP31.P$1
G33
  Top 0.203: IC1.60 48.17,50.71 TP32.P$1
G34
  Top 0.203: IC1.61 47.67,52.25 TP33.P$1
GND  (via drill 0.41, 0.41 pad 0.76)
  Top 0.203: $1_103_$.5 8.62,77.4 8.6,77.37 | 56.35,27.71 54.32,27.71 C19.2 | 56.35,27.71 56.86,27.71 | 56.86,27.71 58.38,27.71 C15.2 | 56.35,27.71 C14.1 | 56.86,27.71 56.86,25.48 IC4.3 | IC3.7 IC3.8 82.72,66.27 v82.72,64.02 | 80.11,72.48 IC3.3 v80.05,69.72 | IC1.10 45.17,33.96 v44.39,34.75 | IC1.20 50.17,34.5 v50.67,35 | IC1.27 55.35,35.35 55.82,34.88 55.82,34.05 v55.95,33.92 | 11.47,73.05 C1.1 | 37.01,24.64 C17.2 | 85.76,94.55 Q6.2 | v37.05,21.5 37.05,24.65 | 59.75,69.98 R41.2 | IC2.1 76.68,37.36 77.08,37.76 77.48,37.76 v77.89,37.35 78.94,37.35 C8.1 | C10.1 R10.2 | C21.2 61.02,45.75 v61.02,47.03 60.41,47.64 C34.2 | R31.2 38.72,27.75 v39.23,28.26 | IC1.99 38.19,35.35 38.01,35.17 38.01,34.96 v37.4,34.35 | 74.67,31.01 v74.84,31.05
  Top 0.254: v83.02,83.12 83,83.1 IC5.4 IC5.3 IC5.2 IC5.1 | 55.47,69.76 R13.2 | C7.1 82.35,33.86 v82.83,34.34 | IC1.74 41.17,49.88
  Top 0.305: R29.2 v58.8,42.01 v58.79,42.02 | R3.2 55.52,61.39 v55.49,61.43 | 41.17,49.88 40.91,50.15 v39.89,50.15 39.99,50.25 C22.2 | R13.2 55.65,71.1 55.69,71.13 v55.69,71.34
  Top 0.406: R41.2 59.78,69.91 59.83,69.86 | 37.05,24.65 C17.2 | v59.55,71.79 59.75,71.59 59.75,69.98 | 85.76,94.55 85,94.55 v84.54,94.09 | IC5.7 v76.01,79.67 | X5.1-8 X5.1-4 | U1.2 36.64,18.05 v36.18,18.5 | C1.1 11.73,72.96 10.58,72.96 10.38,73.16 10.38,74.59 10.21,74.75 C2.1 8.72,75.06 $1_103_$.5 | C10.1 76.62,25.11 C12.1 75.22,25.39 v75.2,25.41 | R24.1 74.67,31.01
  Top 0.508: C1.1 23.29,73.05 32.02,64.33 32.02,60.11 30.42,58.51 30.06,58.51 29.1,58.51 OK1.2
  Top 0.61: 30.14,58.59 30.06,58.51
  Top 0.813: C20.2 37.01,21.54 v37.05,21.5
  Bottom 0.203: C18.1 56.57,25.41 IC4.3 | 54.42,45.49 C30.1 | v50.67,35 50.74,35 | C31.2 71.98,36.56 72.01,36.53 72.01,36.63 | C13.2 C16.2 | 82.88,64.19 v82.72,64.02 | 39.32,36.94 C27.2 | 44.45,53 C23.2 | v80.05,69.72 80.05,69.53 80.07,69.51 | v66.32,43.94 65.52,43.14 R5.1 R40.2 | C24.1 44.03,34.39 v44.39,34.75 | v39.23,28.26 39.43,28.26
  Bottom 0.254: 50.74,35 50.75,35 51.27,35.52 53.3,35.52 53.71,35.12 54.35,35.12 C28.1 | R34.1 72.59,38.17 | v75.2,25.41 74.99,25.41 | LM393.5 LM393.4
  Bottom 0.305: v58.79,42.02 58.79,42.23 | v55.49,61.43 55.69,61.23
  Bottom 0.406: 90.76,11.69 C3.1 | 84.34,93.89 v84.54,94.09 | 75.81,79.67 v76.01,79.67 | C5.2 82.82,34.56 v82.83,34.34 | 72.59,38.17 IC2.P$8 | C29.2 75.54,37.28 IC2.P$2 | IC2.P$10 IC2.P$9
  other vias: 46.42,37.19 50.27,47.2 48.24,46.99 44.38,46.99 40.92,42.73 81.31,98.66 91.26,98.25 97.56,86.06 85.37,46.03 74.86,55.12 98.17,27.33 97.56,36.07 95.12,21.44 97.56,6.81 22.38,9.1 10.39,21.24 1.45,19.2 20.96,21.85 22.38,16.16 24.41,47.45 29.9,51.92 30.91,63.91 81.99,50.42 0.84,0.92 48.24,44.15 50.27,44.15 62.45,50.56 60.49,53.76 62.45,57.26 57.77,61.13 55.74,58.48 54.11,59.5 47.21,56.65 51.47,54.22 49.64,55.03 54.85,53.17 48.24,40.9 50.52,40.9 48.24,38.25 46.22,40.85 46.62,43.89 43.78,40.64 43.98,42.88 41.34,37.19 10.55,16.05 50.53,37.21 50.58,38.67 47.21,59.5 44.56,59.5 40.91,54.42 36.44,53.61 31.71,1.03 31.71,11.8 28.46,23.58 24.4,27.85 23.79,36.79 34.15,47.76 36.59,63 36.39,58.13 40.25,61.38 35.17,68.9 39.23,68.9 41.87,64.43 46.55,82.11 56.71,86.78 54.06,89.62 53.86,75.1 61.81,89.29 69.61,75.6 65.06,91.58 70.52,92.47 66.1,96.41 72.15,90.44 65.04,82.92 65.44,78.65 63.21,74.99 63.21,64.43 63.21,67.68 65.44,67.48 65.44,65.04 72.76,57.72 68.08,57.32 68.08,59.75 64.83,59.35 62.88,32.3 61.58,59.35 50,31.36 54.24,49.9 79.11,77.18 75.86,76.77 76.47,71.08 75.65,58.89 82.77,59.91 67.73,64.99 67.73,67.63 78.44,45.14 72.57,49.43 66.93,54.1 68.35,51.46 77.5,49.18 82.98,55.32 79.38,53.19 73.86,41.63 76.89,17.73 70.79,20.78 56.97,19.76 45.59,19.36 34.62,22.81 29.54,18.75 50.88,24.64 43.56,22.81 45.43,31.48 54.57,22.34 55.84,32.37 61.05,35.55 72.78,31.53 49.54,75.73 77.86,63.79 42.91,56.45 50.66,58.84 61.46,63.03 85.93,24.08 44.46,57.24 82.02,40.01 79.33,42.04 69.93,41.28
  pour Bottom: 23.18,48.58 23.18,23.18 0.01,22.97 0.22,0.01 32.47,0.22 32.47,12.41 35.27,15.71 40.09,15.71 42.89,18 56.86,18 59.4,20.54 69.56,20.28 78.45,10.38 86.32,10.38 86.58,10.12 88.86,7.58 88.61,-0.04 99.76,-0.04 99.86,99.91 48.58,99.78 48.58,83.32 41.47,83.12 41.26,82.72 40.65,82.92 40.65,69.51 28.87,69.51 28.87,68.69 28.66,68.9 28.66,48.78
  pour Top: 48.37,99.99 99.99,99.99 99.99,0.01 88.86,0.01 88.86,7.84 86.32,10.38 78.19,10.38 69.3,20.28 59.4,20.54 56.86,18 43.14,18 40.09,15.71 35.27,15.71 32.47,12.41 32.47,0.22 0.01,0.01 0.01,23.18 23.18,23.18 23.18,48.58 28.66,48.58 28.66,69.51 40.86,69.51 40.86,83.32 48.58,83.32 48.58,99.17
I2C_SCL  (via drill 0.41 pad 0.76)
  Top 0.203: IC1.92 40.3,38.85 41.92,40.47 41.92,44.36 43.5,45.94 43.7,46.14 51.42,46.14 55.41,50.13 v58.79,50.13 | 78.78,71.49 78.78,72 | 78.78,72 IC3.4 78.78,74.12 R30.2 79.75,76.1 v80.28,76.62 | v77.1,60.21 77.1,69.08 78.8,70.78 78.8,71.97 78.78,72 | IC5.6 79.67,80.89 80.28,80.28 v80.28,79.26
  Bottom 0.203: v58.79,50.13 59.17,50.13 62.24,53.2 74.74,53.2 77.1,55.56 v77.1,60.21 | v80.28,76.62 v80.28,79.26
I2C_SDA  (via drill 0.41, 0.41 pad 0.76)
  Top 0.203: IC1.93 40.48,38.35 42.33,40.2 42.33,44.16 43.9,45.73 51.63,45.73 55.28,49.39 56.1,49.39 v56.3,49.19 | v77.86,58.94 78.48,59.16 R32.2 79.26,59.18 79.26,60.16 78.78,60.64 IC3.5
  Top 0.254: IC3.5 78.78,68.19 v78.09,68.87 | v77.89,83.25 78.07,82.42 IC5.5
  Bottom 0.203: v77.86,58.94 77.91,58.28 77.91,55.51 74.94,52.54 62.22,52.54 58.87,49.19 v56.3,49.19
  Bottom 0.254: v78.09,68.87 78.09,83.12 v77.89,83.25
ILI_LED  (via drill 0.41)
  Top 0.203: IC1.96 37.05,36.85 36.18,35.98 36.18,35.62 v36.34,35.47
  Bottom 0.203: v36.34,35.47 32.73,35.47 SV3.8
ILI_MISO
  Top 0.203: IC1.79 31.63,45.35 31,44.72 31,39.13 30.64,38.77 29.27,38.77 28.46,37.96 28.46,33.64 SV3.9
ILI_MOSI
  Top 0.203: IC1.80 35.09,44.85 33.49,43.24 33.49,38.77 SV3.6
ILI_RST  (via drill 0.41)
  Top 0.203: IC1.82 35.72,43.85 34.76,42.89 v34.76,41.31
  Bottom 0.203: v34.76,41.31 34.76,41.06 33.95,40.04 SV3.4
ILI_SCK  (via drill 0.41)
  Top 0.203: IC1.78 30.55,45.85 28.61,43.9 28.61,39.74 v27.7,38.82
  Bottom 0.203: v27.7,38.82 27.7,36.94 SV3.7
INT_0  (via drill 0.41 pad 0.76)
  Top 0.203: IL1.7 IL1.6 | IC1.26 54.39,34.81 53.45,34.81 52.87,35.39 v52.87,37.35 | v67.12,48.93 67.12,51.37 66.51,51.98 64.9,51.98 R12.1 | v67.12,47.1 67.12,46.9 65.29,45.07 64.53,45.07 v64.48,45.02
  Top 0.254: IL1.6 55.01,90.91 66.46,79.46 66.46,55.89 64.83,54.27 R12.1 65.29,52.09
  Bottom 0.203: v64.48,45.02 58.43,45.02 57.77,44.36 57.77,38.57 57.16,37.96 53.48,37.96 v52.87,37.35 52.9,37.38 | v67.12,47.1 v67.12,48.93
INT_IR  (via drill 0.41, 0.41 pad 0.76)
  Top 0.203: IC1.35 52.96,39.35 52.03,38.42 52.03,35.09 v52.34,34.78 52.26,34.86
  Top 0.406: v52.29,24.19 52.29,23.13 50.51,21.35 42.02,21.35 41.11,20.43 32.83,20.43 30.09,17.69 30.09,14.64 26.84,11.39 26.84,2.43 X1.3
  Bottom 0.203: v52.34,34.78 52.34,24.24 v52.29,24.19
L  (via drill 0.6 pad 1.27, 0.8 pad 1.68)
  Top 0.203: L.1 6.63,94.65 arc90 U$1.A1
  Top 0.61: 13.2,55.79 14.97,55.79 R33.1
  Top 0.813: R35.1 11.98,38.77 | v1.99,95.97 3.93,94.45 L.1 | 20.66,55.66 OK1.6 | 12.27,55.66 R33.1 | R8.1 33.15,96.23 | 15.66,29.81 OK3.6
  Top 1.016: 11.98,38.77 OK2.6 | v8.9,69.18 8.9,60.08 13.2,55.79 | R33.1 20.66,55.66 | R35.1 9.82,40.94 9.82,53.2 12.27,55.66 | 33.15,96.23 R44.1 | R38.1 11.27,31.03 12.41,29.88 15.58,29.88 OK3.6
  Bottom 0.813: R44.1 26.23,95.97 | OK2.6 17.13,38.77 17.89,38.01 17.89,30.49 17.08,29.68 15.79,29.68 OK3.6
  Bottom 1.016: v8.9,69.18 14.92,69.18 17.92,72.17 17.92,86.17 | 17.92,86.17 17.92,91.28 22.77,96.13 26.38,96.13 R44.1 | v1.99,95.97 1.99,92.93 8.55,86.37 17.72,86.37 17.92,86.17
  pour Top (no thermals): 8.95,99.78 0.22,99.78 0.22,89.62 8.95,89.62
LED_ETH_ACT  (via drill 0.41, 0.41 pad 0.76)
  Top 0.203: v77.98,33.92 77.9,33.92 IC2.30
  Top 0.254: v84.95,32.93 81.09,32.93 80.28,32.12 v80.28,31.71
  Bottom 0.254: v77.98,33.92 77.98,33.09 79.36,31.71 v80.28,31.71 | RJ1.Y- 97.78,41.26 91.25,41.26 88.51,38.52 88.51,37.71 88.2,37.4 86.37,37.4 85.97,36.99 85.97,33.95 v84.95,32.93
LED_ETH_LINK  (via drill 0.41, 0.41 pad 0.76)
  Top 0.203: IC2.31 77.27,35.26 78.02,35.26 v78.42,34.85
  Top 0.406: RJ1.G- 97.88,34.76 92.47,34.76 88.41,30.7 82.36,30.7 v81.39,31.66 81.44,31.71
  Bottom 0.406: v81.39,31.66 81.39,31.88 v78.42,34.85
LT
  Top 0.203: $1_103_$.1 12.41,82.65 11.27,82.65 $1_103_$.2 arc90 12.35,83.72 12.34,84.29 U$1.A2
  Top 0.813: 12.34,83.39 12.34,84.29 | C32.1 23.26,82.64
  Top 1.016: R6.2 26.43,82.38 C32.1 | 23.26,82.64 $1_103_$.1
  pour Top (no thermals): 10.99,81.29 14.85,81.29 14.85,99.78 10.99,99.78
MOTOR  (via drill 0.41)
  Top 0.203: IC1.64 46.17,47.55 v45.53,46.9 | v45.07,44.62 45.07,42.63 44.51,42.08 44.51,38.42 43.5,37.4 v43.5,36.74
  Top 0.254: R4.1 41.01,18.47 v42.02,18.61
  Bottom 0.203: 42.13,21.35 42.13,31.56 42.63,32.02 42.63,35.67 v43.5,36.74 | v45.07,44.62 45.07,46.24 v45.53,46.9
  Bottom 0.254: 42.13,21.35 42.13,18.71 v42.02,18.61
MPX  (via drill 0.41, 0.41 pad 0.76)
  Top 0.203: R41.1 59.78,64.77 R19.2 61.06,64.74 v61.12,64.68 | IC1.29 65.64,36.35 v65.98,36.01 | v63.44,42.56 63.44,59.42 v62.75,60.11
  Bottom 0.203: v65.98,36.01 63.44,38.55 v63.44,42.56 | v62.75,60.11 62.75,63.03 61.12,64.66 v61.12,64.68
MPX_CON  (via drill 0.41)
  Top 0.203: 91.85,58.51 X5.1-3
  Top 0.254: R19.1 v59.8,61.58 | v86.12,57.01 85.71,56.6 72.1,56.6 v69.96,58.74
  Top 0.406: X6.1-7 X6.1-3 92.94,77.67 97.75,72.86 97.75,61.81 94.45,58.51 91.85,58.51 | X5.1-7 X5.1-3
  Bottom 0.203: 60.41,58.43 69.36,58.43 v69.96,58.74
  Bottom 0.254: v59.8,61.58 59.8,59.04 60.41,58.43 | v86.12,57.01 87.51,57.01 X5.1-7
N
  Bottom 1.016: X3.5 2.98,66.94 | 2.98,66.94 X3.4 | 2.98,66.94 18.43,66.94 26.25,74.77 26.25,81.38 R9.1
N$1
  Top 0.203: Q7.1 80.05,63.04 IC3.6
N$2
  Bottom 0.406: Q5.3 97.69,94.03 97.95,94.3 97.95,97.01 SG1.-
N$3
  Bottom 0.203: Q5.1 94.28,91 R16.2
N$4
  Top 0.406: Q6.3 88.17,93.12 COOLER.2
N$5
  Top 0.203: 83.03,96.68 R17.2
  Top 0.406: Q6.1 83.03,96.68
N$6  (via drill 0.41 pad 0.76)
  Top 0.203: IC2.10 73.06,39.5 71.98,40.58 v71.98,41.62
  Bottom 0.203: v71.98,41.62 73.25,40.35 R34.2
N$7
  Top 0.254: 39.41,17.18 U1.1
  Top 0.406: R4.2 39.18,18.61 U1.1
N$8
  Top 0.203: IC2.2 76.82,38.21 80.28,38.21 80.68,37.81 80.68,37.31 C8.2
  Top 0.254: C8.2 80.72,35.63 C7.2
N$9
  Top 0.203: 74.22,39.84 IC2.8 74.77,40.42 74.77,43.4 76.16,44.79 Q1.1
  Bottom 0.406: C9.1 76.24,46.75 Q1.1
N$10
  Top 0.203: 73.4,39.91 IC2.9 72.86,40.38 72.86,43.4 Q1.2
  Bottom 0.406: C11.1 71.41,46.73 Q1.2
N$11
  Top 0.203: IC2.5 76.51,40.04 79.57,40.04 83.45,36.16 RJ1.RD+
N$12
  Top 0.203: IC2.6 76.2,40.45 80.28,40.45 82.11,38.62 85.46,38.62 86.68,37.4 87.9,37.4 88.51,36.79 88.51,35.62 87.85,34.96 84.87,34.96 RJ1.TD- 84.82,34.86
N$13
  Top 0.203: IC2.7 75.95,40.91 83.93,40.91 84.39,41.36 85.36,41.36 86.73,39.99 88.56,39.99 89.37,39.18 89.37,35.65 RJ1.TD+
N$14
  Bottom 0.406: C5.1 84.58,37.21 RJ1.P4
N$15  (via drill 0.41)
  Top 0.203: IC2.4 76.81,39.64 78.91,39.64 v79.57,38.98
  Bottom 0.203: v79.57,38.98 83.81,38.98 RJ1.RD-
N$16
  Bottom 0.203: RJ1.P5 87.31,38.72 87.31,39.41 85.61,41.11 82.36,41.11 81.8,41.67 C6.1
N$17
  Bottom 0.813: R8.2 41.26,96.27 IL1.1 | 38.12,95.99 38.01,96.1 | 41.43,91.02 IL1.3
  Bottom 1.016: IL1.1 38.12,95.99 | 38.01,96.1 38.01,91.53 38.52,91.02 41.43,91.02
N$18  (via drill 0.6)
  Top 0.61: 52.59,2.45 U$4.2 53.74,1.49 64.48,1.49 66.76,3.77 | C47.- 66.76,3.77 | 66.76,3.77 69.3,1.23 70.73,1.23 R21.2 v72.78,1.31
  Bottom 0.406: C46.1 78.53,8.19 U$5.1
  Bottom 0.61: v72.78,1.31 77.86,1.31 78.52,1.97 78.52,2.9 U$5.1
N$19
  Top 0.61: X5.M3 X5.M1 | X5.M4 X5.M2
  Bottom 0.61: X5.M3 84.54,55.28 84.54,59.96 X5.M4
N$20
  Top 0.406: Q4.2 37.68,4.15 | 37.68,4.15 38.01,4.48 R7.2 | Q4.4 37.58,1.61 38.01,2.05 38.01,3.82 37.68,4.15
N$21
  Top 1.016: C32.2 24.65,91.15 R44.2
N$22
  Bottom 0.406: R42.1 95.02,35.08 RJ1.G+
N$23
  Bottom 0.203: 89.15,9.8 R15.2 | 88.96,11.59 C3.2 | 88.46,14.39 87.93,14.24 LM393.3
  Bottom 0.254: LM393.6 84.13,14.37 84.62,14.85
  Bottom 0.406: 89.15,9.8 C3.2 89.22,11.85 89.22,12.41 89.62,12.81 89.62,13.83 89.27,14.34 88.46,14.39 | R14.1 85.71,17.64 84.34,16.47 84.34,15.05 84.62,14.85 85.31,14.39 87.62,14.39 LM393.3
N$24
  Bottom 0.406: LM393.2 90.62,15.63 C4.2 | C4.2 90.72,19.44 JP1.D- | R18.2 94.46,12.45 92.47,14.44 92.47,15.05 91.86,15.66 90.79,15.66 C4.2
N$26
  Top 0.203: 81.7,59.12 R27.2 80.46,60.04 Q7.2 80.42,60.92
N$27
  Top 0.406: X6.1-8 X6.1-4
N$28
  Top 0.406: U1.4 37.91,9.14 R7.1
N$29
  Top 0.203: OK1.1 31.8,56.22 R36.2
N$30
  Top 0.203: R37.2 26.5,27.2 26.5,37.43 25.16,38.77 OK2.1
N$31
  Bottom 0.61: 33.2,77.04 MOC3023.6
  Bottom 1.016: R6.1 33.2,77.04
N$32
  Top 0.203: $1_103_$.7 11.26,76.29 11.77,75.78 25.44,75.78 38.16,63.06 42.53,63.06 51.88,72.4 56.96,72.4 57.7,71.67 57.72,71.67 | 57.72,71.59 57.72,69.95 R11.1
  Top 0.254: 57.72,71.59 57.72,71.67 57.72,71.74
N$33
  Top 0.813: 38.01,88.22 R9.2
  Top 1.016: IL1.2 38.92,93.45 38.01,92.55 38.01,88.22
  Bottom 0.813: 41.31,88.14 IL1.4
  Bottom 1.016: R9.2 41.31,88.14
N$34
  Top 0.813: 5.98,40.35 R35.2
  Top 1.016: C39.2 5.98,40.35
N$35
  Top 0.203: MOC3023.1 43.12,77 43.5,76.62 43.5,74.59 42.08,73.16 42.08,72.15 R1.2
N$36
  Top 0.203: 10.05,77.4 $1_103_$.6 9.99,76.58 C1.2
N$37
  Top 0.813: R33.2 14.56,61.26
  Top 1.016: 14.56,61.26 C38.2
N$38
  Top 0.61: R21.1 72.48,4.18 74.31,2.35 79.16,2.35 80.2,3.39 80.2,5.4 X7.2
N$39  (via drill 0.41 pad 0.76)
  Top 0.406: v96.15,39.23 96.15,42.18 RJ1.Y+
  Bottom 0.203: R43.1 96.13,39.2 v96.15,39.23
N$42
  Bottom 0.813: 21.17,61.35 OK1.4
  Bottom 1.016: X3.3 14.92,59.45 16.83,61.35 21.17,61.35 | C38.1 21.3,63.72 OK1.4
N$43
  Bottom 0.813: 12.15,43.93 C39.1 | 15.69,43.75 OK2.4
  Bottom 1.016: X3.2 6.77,54.37 12.15,48.98 12.15,43.93 | C39.1 15.69,43.75
N$44
  Top 0.203: OK3.1 23.3,26.24 R39.2
N$45
  Top 0.813: 2.65,29.98 R38.2
  Top 1.016: C40.2 2.65,29.98
N$48
  Bottom 0.813: OK3.4 12.51,34.86 C40.1 8.09,38.37 8.09,46.7
  Bottom 1.016: 8.09,46.7 5.5,49.29 X3.1
OSC32_IN
  Top 0.203: IC1.8 44.17,31.37 40.65,27.85 40.65,25.02 Q3.1 | 38.85,24.55 40.3,24.55 40.62,24.88 Q3.1 | 40.7,25.07 Q3.1
  Top 0.254: 38.85,24.55 C17.1
OSC32_OUT
  Top 0.203: IC1.9 44.67,31.06 42.2,28.59 42.2,23.22 Q3.2 38.77,22.45
  Top 0.254: 38.77,22.45 C20.1
OSC_IN
  Top 0.254: IC1.12 46.17,30.88 Q2.1
  Bottom 0.203: C13.1 43.94,26.88
  Bottom 0.305: 43.94,26.88 Q2.1
OSC_OUT
  Top 0.254: IC1.13 46.67,30.81 Q2.2
  Bottom 0.203: C16.1 48.77,26.88
  Bottom 0.305: 48.77,26.88 Q2.2
PHY_INTRP  (via drill 0.41 pad 0.76)
  Top 0.203: IC1.31 66.88,37.35 v69.56,34.79 | v70.75,33.29 70.71,33.48 IC2.21
  Bottom 0.203: v69.56,34.79 69.47,34.81 v70.75,33.29
PHY_RST  (via drill 0.41, 0.41 pad 0.76)
  Top 0.203: IC1.30 66.17,36.85 v67.55,35.46 | IC2.32 77.1,36.17 78.25,36.17 79.26,35.17 79.26,29.6 79.06,29.4 | 76.01,29.48 v75.81,29.68
  Top 0.254: 76.01,29.48 77.09,29.48 R23.2
  Top 0.406: C12.2 79.67,25.82 79.67,29.27 79.54,29.4 79.06,29.4 R23.2
  Bottom 0.203: v67.55,35.46 67.55,34.68 68.34,33.9 69.15,33.9 70.78,32.27 70.78,30.04 71.21,29.61 75.73,29.61
  Bottom 0.254: 75.73,29.61 v75.81,29.68
RST  (via drill 0.41)
  Top 0.203: IC1.14 47.17,36 47.36,36.18 47.36,44.67 v47.31,44.72
  Bottom 0.203: SV2.1 51.52,60.44 51.52,58.38 47.1,53.96 | 44.56,54.79 C23.1 | C23.1 44.73,54.62 46.44,54.62 47.1,53.96 | 44.16,54.69 44.56,54.69 C23.1 | v47.31,44.72 47.31,53.76 47.1,53.96
  Bottom 0.254: R22.2 44.16,54.69
SPIRT  (via drill 0.41, 0.41 pad 0.76)
  Top 0.203: R36.1 32.2,52.26 35.62,48.83 36.54,48.83 v36.59,48.88 | IC1.40 52.47,41.85 v52.03,41.87
  Bottom 0.203: v36.59,48.88 36.74,48.73 37.25,48.73 37.86,48.12 37.86,47.31 43.34,41.82 52.18,41.82 v52.03,41.87
SWCLK
  Top 0.203: IC1.76 38.24,46.85 37.63,47.46 37.63,54.75 43.45,60.57 48.86,60.57 SV2.2
SWDIO
  Top 0.203: SV2.4 48.88,62.42 50.18,61.12 50.18,59.37 49.34,58.53 43.65,58.53 42.15,57.04 42.15,48.62 IC1.72
T
  Top 0.203: $1_103_$.3 $1_103_$.4 7.6,82.64
  Top 0.61: T.1 7.08,83.15 7.6,82.64
  pour Top (no thermals): 10.17,81.29 10.17,85.15 8.95,86.37 0.22,86.37 0.22,81.29
T_CLK  (via drill 0.41)
  Top 0.203: IC1.89 37.5,40.35 36.59,39.43 36.59,38.21 34.35,35.98 34.35,34.76 v34.3,34.71
  Bottom 0.203: v34.3,34.71 34.3,34.51 SV3.10
T_CS  (via drill 0.41)
  Top 0.203: IC1.87 36.67,41.35 35.57,40.25 35.57,39.08 v35.06,38.57
  Bottom 0.203: v35.06,38.57 35.06,38.52 32.83,36.28 31.71,36.28 30.95,35.52 30.95,31.15 SV3.11
T_DIN(MOSI)  (via drill 0.41)
  Top 0.203: IC1.91 39.95,39.35 40.65,40.04 40.65,40.65 v40.86,40.86
  Bottom 0.203: v40.86,40.86 40.86,40.25 40.04,39.43 38.01,39.43 37.81,39.23 37.81,35.98 33.54,31.71 33.54,30.29 33.13,29.88 SV3.12
T_DO(MISO)  (via drill 0.41)
  Top 0.203: IC1.90 37.61,39.85 37.2,39.43 37.2,38.21 34.96,35.98 34.96,33.34 34.25,32.63 34.25,29.38 v34.56,29.07
  Bottom 0.203: v34.56,29.07 33.95,29.07 33.54,28.66 31,28.66 SV3.13
T_IRQ
  Top 0.203: SV3.14 33.54,28.66 33.54,35.98 36.18,38.62 36.18,40.04 36.98,40.85 IC1.88
TRIAC  (via drill 0.41, 0.41 pad 0.76)
  Top 0.203: R1.1 41.99,68.78 v40.42,67.22 | IC1.65 45.67,55.83 v46.14,56.3
  Bottom 0.203: v46.14,56.3 46.14,59.65 44.62,61.18 43.55,61.18 40.5,64.22 40.45,67.2 v40.42,67.22
TRIAC_V
  Top 0.813: 17.77,95.37 U$1.G3 17.97,95.2 | 31.84,82.08 MOC3023.4
  Top 1.016: 17.97,95.2 17.97,89.01 21.43,85.56 28.36,85.56 31.84,82.08
USART1_RX
  Top 0.203: 50.18,64.38 50.18,62.37 50.81,61.73 52.44,61.73 52.79,61.38 52.79,59.65 51.17,58.03 44.21,58.03 43.67,57.49 IC1.69
  Top 0.254: 50.18,64.38 SV2.5
USART1_TX
  Top 0.203: 52.41,63.08 53.25,62.24 53.25,59.42 51.35,57.52 45.68,57.52 44.17,56.01 IC1.68
  Top 0.254: 52.41,63.08 SV2.3
VBAT  (via drill 0.41 pad 0.76)
  Top 0.203: v46.39,52.18 46.39,54.62 48.27,56.5 56.05,56.5 62.19,62.65 62.19,77.95 BAT1.1 | v44.56,37.25 44.92,37.61 44.92,41.87 45.53,42.48 45.53,43.9 45.94,44.31 45.94,44.62 v46.19,44.87 | IC1.6 43.17,34.74 v43.34,34.91
  Bottom 0.203: v46.39,52.18 46.39,45.07 v46.19,44.87 | v43.34,34.91 43.45,34.91 44.31,35.78 44.31,36.99 v44.56,37.25
VCAP_1
  Top 0.203: IC1.49 57.11,46.35 58.13,45.33 58.9,45.33 C21.1
VCAP_2
  Top 0.203: IC1.73 41.67,52.23 40.91,53 40.02,53 C22.1
VREF
  Top 0.203: 60.64,27.65 R28.2 60.5,24.07 59.44,23 IC4.2 56.45,23 53.11,26.34 53.11,29.53 50.67,31.96 IC1.21
  Bottom 0.203: C18.2 58.05,27.38 IC4.2
WATER  (via drill 0.41)
  Top 0.203: IC1.41 53.18,42.35 v52.84,42.69 | 23.41,24.44 R39.1 23.33,24.41 23.33,23.48 24.04,22.77 30.64,22.77 38.62,30.75 v38.62,31.91
  Bottom 0.203: 38.77,32.12 v38.62,31.91 40.45,33.95 40.86,33.95 41.67,34.76 41.67,36.39 42.08,36.79 42.08,36.99 44.87,39.79 50.76,39.79 51.63,40.65 52.23,40.65 52.84,41.26 v52.84,42.69

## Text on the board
tNames: + | 5V | - | - | D | +5V | +5V | N | LabSpirt V5.0 | GND | SWDIO | Spirt | SWCLK | Dimrot | Water | +24V | OUT | -24V | - | - | D | +5V
bNames: LabSpirt V5.0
